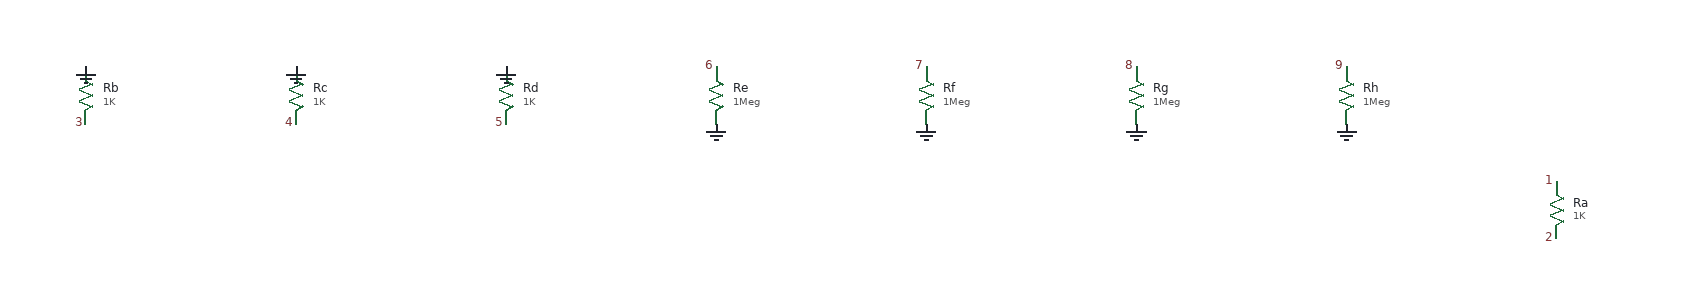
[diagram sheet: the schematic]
v {xschem version=3.4.5 file_version=1.2}
G {}
K {}
V {}
S {}
E {}
C {devices/res.sym} 1980 -280 0 0 {name=Ra
value=1K}
C {devices/res.sym} 440 -400 0 0 {name=Rb
value=1K}
C {devices/res.sym} 660 -400 0 0 {name=Rc
value=1K}
C {devices/res.sym} 880 -400 0 0 {name=Rd
value=1K}
C {devices/res.sym} 1100 -400 0 0 {name=Re
value=1Meg}
C {devices/res.sym} 1320 -400 0 0 {name=Rf
value=1Meg}
C {devices/res.sym} 1540 -400 0 0 {name=Rg
value=1Meg}
C {devices/res.sym} 1760 -400 0 0 {name=Rh
value=1Meg}
C {devices/lab_pin.sym} 1980 -310 0 0 {name=l_1 sig_type=std_logic lab=1}
C {devices/lab_pin.sym} 1980 -250 0 0 {name=l_2 sig_type=std_logic lab=2}
C {devices/gnd.sym} 440 -430 0 0 {name=l_0 lab=GND}
C {devices/gnd.sym} 660 -430 0 0 {name=l_0 lab=GND}
C {devices/gnd.sym} 880 -430 0 0 {name=l_0 lab=GND}
C {devices/gnd.sym} 1100 -370 0 0 {name=l_0 lab=GND}
C {devices/gnd.sym} 1320 -370 0 0 {name=l_0 lab=GND}
C {devices/gnd.sym} 1540 -370 0 0 {name=l_0 lab=GND}
C {devices/gnd.sym} 1760 -370 0 0 {name=l_0 lab=GND}
C {devices/lab_pin.sym} 440 -370 0 0 {name=l_3 sig_type=std_logic lab=3}
C {devices/lab_pin.sym} 660 -370 0 0 {name=l_4 sig_type=std_logic lab=4}
C {devices/lab_pin.sym} 880 -370 0 0 {name=l_5 sig_type=std_logic lab=5}
C {devices/lab_pin.sym} 1100 -430 0 0 {name=l_6 sig_type=std_logic lab=6}
C {devices/lab_pin.sym} 1320 -430 0 0 {name=l_7 sig_type=std_logic lab=7}
C {devices/lab_pin.sym} 1540 -430 0 0 {name=l_8 sig_type=std_logic lab=8}
C {devices/lab_pin.sym} 1760 -430 0 0 {name=l_9 sig_type=std_logic lab=9}
